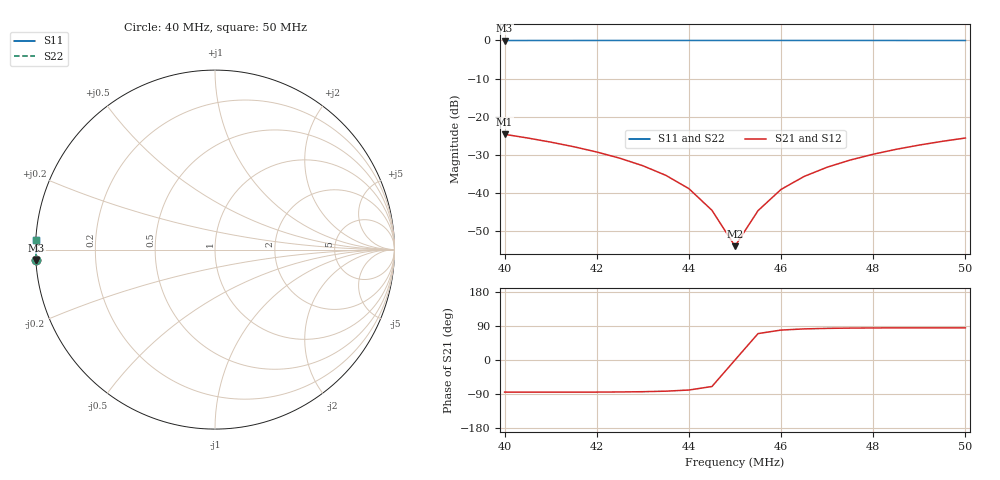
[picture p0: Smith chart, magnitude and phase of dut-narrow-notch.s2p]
! Parameter plane de-embed bench export
! Network: dut-narrow-notch
! PortZ0: 50+0j 50+0j
# mhz S RI R 50
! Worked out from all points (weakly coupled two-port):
!   21 points, 40 MHz to 50 MHz, reference 50 ohm
!   highest |S21| = -24.65 dB at 40 MHz (marker M1); lowest = -54.0 dB at 45 MHz (marker M2)
!   lowest |S11| = 0.0 dB at 40 MHz (marker M3), VSWR 538.53, Z = 0.0929 - j1.46 ohm
!   |S11| at or under -10 dB: nowhere
!   |S22| runs from 0.0 to 0.0 dB; largest |S21 - S12| = 0
40  -0.9946 -0.0583  0.00541 -0.0583  0.00541 -0.0583  -0.9946 -0.0583
40.5  -0.9953 -0.0522  0.00473 -0.0522  0.00473 -0.0522  -0.9953 -0.0522
41  -0.9959 -0.0461  0.00413 -0.0461  0.00413 -0.0461  -0.9959 -0.0461
41.5  -0.9964 -0.0401  0.00361 -0.0401  0.00361 -0.0401  -0.9964 -0.0401
42  -0.9968 -0.0342  0.00317 -0.0342  0.00317 -0.0342  -0.9968 -0.0342
42.5  -0.9972 -0.0283  0.0028 -0.0283  0.0028 -0.0283  -0.9972 -0.0283
43  -0.9975 -0.0225  0.0025 -0.0225  0.0025 -0.0225  -0.9975 -0.0225
43.5  -0.9977 -0.0168  0.00228 -0.0168  0.00228 -0.0168  -0.9977 -0.0168
44  -0.9979 -0.0111  0.00212 -0.0111  0.00212 -0.0111  -0.9979 -0.0111
44.5  -0.998 -0.00554  0.00203 -0.00554  0.00203 -0.00554  -0.998 -0.00554
45  -0.998 0  0.002 0  0.002 0  -0.998 0
45.5  -0.998 0.00548  0.00203 0.00548  0.00203 0.00548  -0.998 0.00548
46  -0.9979 0.0109  0.00211 0.0109  0.00211 0.0109  -0.9979 0.0109
46.5  -0.9977 0.0163  0.00226 0.0163  0.00226 0.0163  -0.9977 0.0163
47  -0.9975 0.0215  0.00246 0.0215  0.00246 0.0215  -0.9975 0.0215
47.5  -0.9973 0.0268  0.00272 0.0268  0.00272 0.0268  -0.9973 0.0268
48  -0.997 0.032  0.00302 0.032  0.00302 0.032  -0.997 0.032
48.5  -0.9966 0.0371  0.00338 0.0371  0.00338 0.0371  -0.9966 0.0371
49  -0.9962 0.0422  0.00378 0.0422  0.00378 0.0422  -0.9962 0.0422
49.5  -0.9958 0.0472  0.00423 0.0472  0.00423 0.0472  -0.9958 0.0472
50  -0.9953 0.0522  0.00473 0.0522  0.00473 0.0522  -0.9953 0.0522
